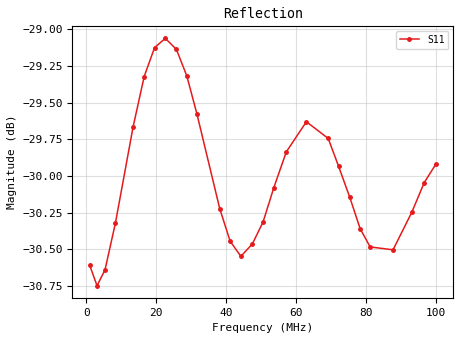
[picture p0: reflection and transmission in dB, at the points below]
# MHz S RI R 50.0
! SimSmith 18.4g
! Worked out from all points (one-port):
!   1000 points, 1 MHz to 100 MHz, reference 50 ohm
!   lowest |S11| = -30.7 dB at 3.081 MHz (marker M1), VSWR 1.06, Z = 47.6 + j1.56 ohm
!   |S11| at or under -10 dB: start of sweep to end of sweep
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1  -0.0288 0.00628
3.081081  -0.024 0.0163
5.36036  -0.0159 0.0247
8.333333  -0.00209 0.0304
13.38739  0.0219 0.0245
16.55856  0.0319 0.0123
19.53153  0.0349 -0.00226
22.6036  0.0308 -0.0171
25.77478  0.0199 -0.0287
28.74775  0.00586 -0.0337
31.62162  -0.0085 -0.0321
38.16216  -0.0296 -0.00859
41.13513  -0.0294 0.00618
44.20721  -0.0223 0.0196
47.47748  -0.00898 0.0286
50.54955  0.00602 0.0299
53.62162  0.0199 0.0242
57.18919  0.0305 0.0104
62.93694  0.0284 -0.0168
69.18018  0.00329 -0.0324
72.15315  -0.011 -0.0299
75.32432  -0.0233 -0.0206
78.2973  -0.0294 -0.0075
81.17117  -0.0292 0.00647
87.71171  -0.00817 0.0287
93.06306  0.017 0.0256
96.63063  0.0286 0.0131
100  0.0318 -0.00279
